One B-rep face of a CAD part: STEP entity #205.
In plain terms, the planar face has unit normal (1, 0, 0).
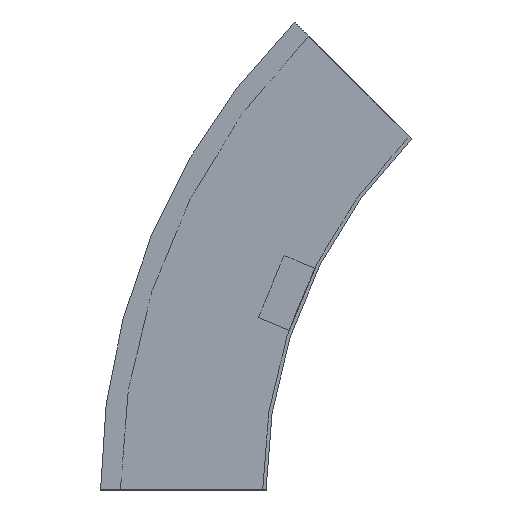
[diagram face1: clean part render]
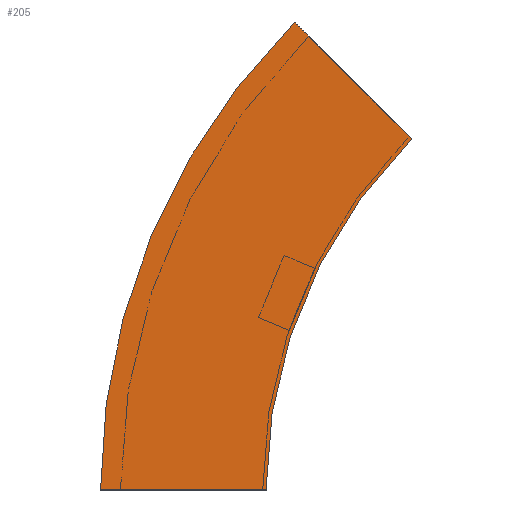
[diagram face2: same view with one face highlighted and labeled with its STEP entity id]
Its self-contained STEP definition (entity closure, numbers rounded to 3 decimals):
#13 = ORIENTED_EDGE ( 'NONE', *, *, #371, .T. ) ;
#16 = VERTEX_POINT ( 'NONE', #312 ) ;
#24 = DIRECTION ( 'NONE',  ( 0., 1., 0. ) ) ;
#70 = LINE ( 'NONE', #117, #72 ) ;
#72 = VECTOR ( 'NONE', #457, 1000. ) ;
#82 = VERTEX_POINT ( 'NONE', #511 ) ;
#100 = DIRECTION ( 'NONE',  ( 0., 1., 0. ) ) ;
#107 = ORIENTED_EDGE ( 'NONE', *, *, #264, .F. ) ;
#117 = CARTESIAN_POINT ( 'NONE',  ( 0., -87.868, 212.132 ) ) ;
#138 = VERTEX_POINT ( 'NONE', #507 ) ;
#146 = DIRECTION ( 'NONE',  ( 1., 0., 0. ) ) ;
#151 = CARTESIAN_POINT ( 'NONE',  ( 0., -17.157, 282.843 ) ) ;
#160 = CARTESIAN_POINT ( 'NONE',  ( 0., -300., 0. ) ) ;
#164 = CARTESIAN_POINT ( 'NONE',  ( 0., 0., 0. ) ) ;
#173 = EDGE_LOOP ( 'NONE', ( #420, #389, #107, #13 ) ) ;
#205 = ADVANCED_FACE ( 'NONE', ( #521 ), #367, .T. ) ;
#206 = EDGE_CURVE ( 'NONE', #138, #429, #70, .T. ) ;
#248 = CIRCLE ( 'NONE', #470, 400. ) ;
#264 = EDGE_CURVE ( 'NONE', #16, #138, #553, .T. ) ;
#278 = DIRECTION ( 'NONE',  ( 1., 0., 0. ) ) ;
#312 = CARTESIAN_POINT ( 'NONE',  ( 0., 0., 0. ) ) ;
#315 = VECTOR ( 'NONE', #24, 1000. ) ;
#319 = CARTESIAN_POINT ( 'NONE',  ( 0., -300., 0. ) ) ;
#322 = EDGE_CURVE ( 'NONE', #82, #429, #248, .T. ) ;
#325 = DIRECTION ( 'NONE',  ( 0., 1., 0. ) ) ;
#341 = AXIS2_PLACEMENT_3D ( 'NONE', #160, #278, #325 ) ;
#358 = DIRECTION ( 'NONE',  ( 0., 0., -1. ) ) ;
#364 = DIRECTION ( 'NONE',  ( 1., 0., 0. ) ) ;
#367 = PLANE ( 'NONE',  #515 ) ;
#371 = EDGE_CURVE ( 'NONE', #16, #82, #397, .T. ) ;
#389 = ORIENTED_EDGE ( 'NONE', *, *, #206, .F. ) ;
#397 = LINE ( 'NONE', #532, #315 ) ;
#420 = ORIENTED_EDGE ( 'NONE', *, *, #322, .T. ) ;
#429 = VERTEX_POINT ( 'NONE', #151 ) ;
#457 = DIRECTION ( 'NONE',  ( 0., 0.707, 0.707 ) ) ;
#470 = AXIS2_PLACEMENT_3D ( 'NONE', #319, #146, #100 ) ;
#507 = CARTESIAN_POINT ( 'NONE',  ( 0., -87.868, 212.132 ) ) ;
#511 = CARTESIAN_POINT ( 'NONE',  ( 0., 100., 0. ) ) ;
#515 = AXIS2_PLACEMENT_3D ( 'NONE', #164, #364, #358 ) ;
#521 = FACE_OUTER_BOUND ( 'NONE', #173, .T. ) ;
#532 = CARTESIAN_POINT ( 'NONE',  ( 0., 0., 0. ) ) ;
#553 = CIRCLE ( 'NONE', #341, 300. ) ;
